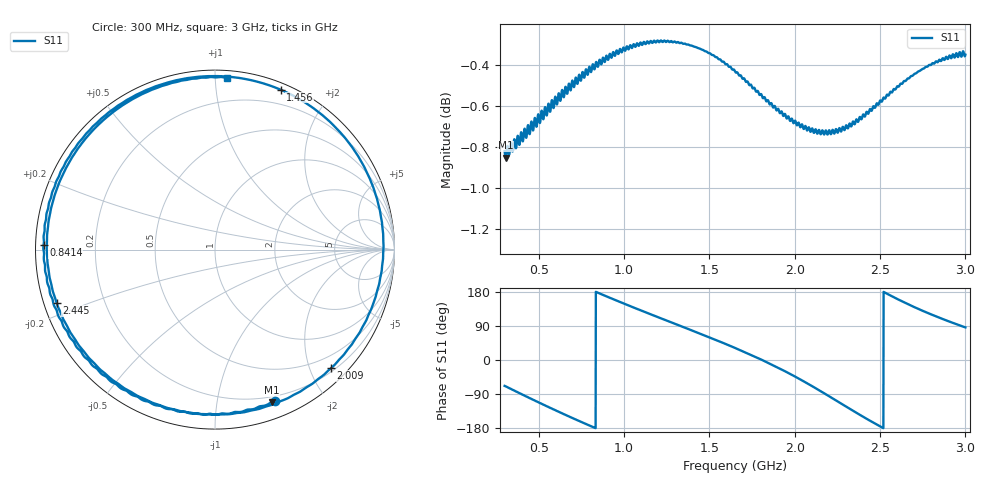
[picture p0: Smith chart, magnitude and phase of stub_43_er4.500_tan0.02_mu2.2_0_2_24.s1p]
! Chirptenna · simulación 3D de un stub abierto
# HZ S RI R 50
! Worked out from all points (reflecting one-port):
!   2001 points, 300 MHz to 3 GHz, reference 50 ohm
!   lowest |S11| = -0.9 dB at 306.8 MHz (marker M1), VSWR 20.40, Z = 7.48 - j71.3 ohm
!   phase of S11 starts at -68 deg and turns -566 deg over the sweep
!   S11 on the Smith chart (normalised r, x): 300 MHz: 0.15, -1.46; 841.4 MHz: 0.02, +0.01; 1.456 GHz: 0.06, +1.49; 2.009 GHz: 0.26, -2.36; 2.445 GHz: 0.04, -0.16; 3 GHz: 0.04, +1.07
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3e8  0.3364 -0.8454
3.0675e8  0.3151 -0.85
3.864e8  0.0423 -0.9121
4.6605e8  -0.2341 -0.8902
5.457e8  -0.4888 -0.7891
6.375e8  -0.7307 -0.5938
7.455e8  -0.904 -0.2804
8.4135e8  -0.9549 0.0262
9.75e8  -0.8608 0.4322
1.14915e9  -0.5097 0.8214
1.3125e9  -0.0507 0.9658
1.4556e9  0.3654 0.891
1.55145e9  0.6114 0.7377
1.65e9  0.8079 0.5024
1.7391e9  0.9144 0.2358
1.82955e9  0.9336 -0.0711
1.91055e9  0.8608 -0.3516
1.9875e9  0.706 -0.5985
2.0091e9  0.647 -0.6595
2.09415e9  0.3596 -0.8466
2.17245e9  0.0355 -0.9177
2.2494e9  -0.2963 -0.8705
2.325e9  -0.5874 -0.7128
2.44515e9  -0.8825 -0.2971
2.5491e9  -0.9315 0.1153
2.6625e9  -0.7993 0.5091
2.82315e9  -0.4191 0.8595
3e9  0.0661 0.958
